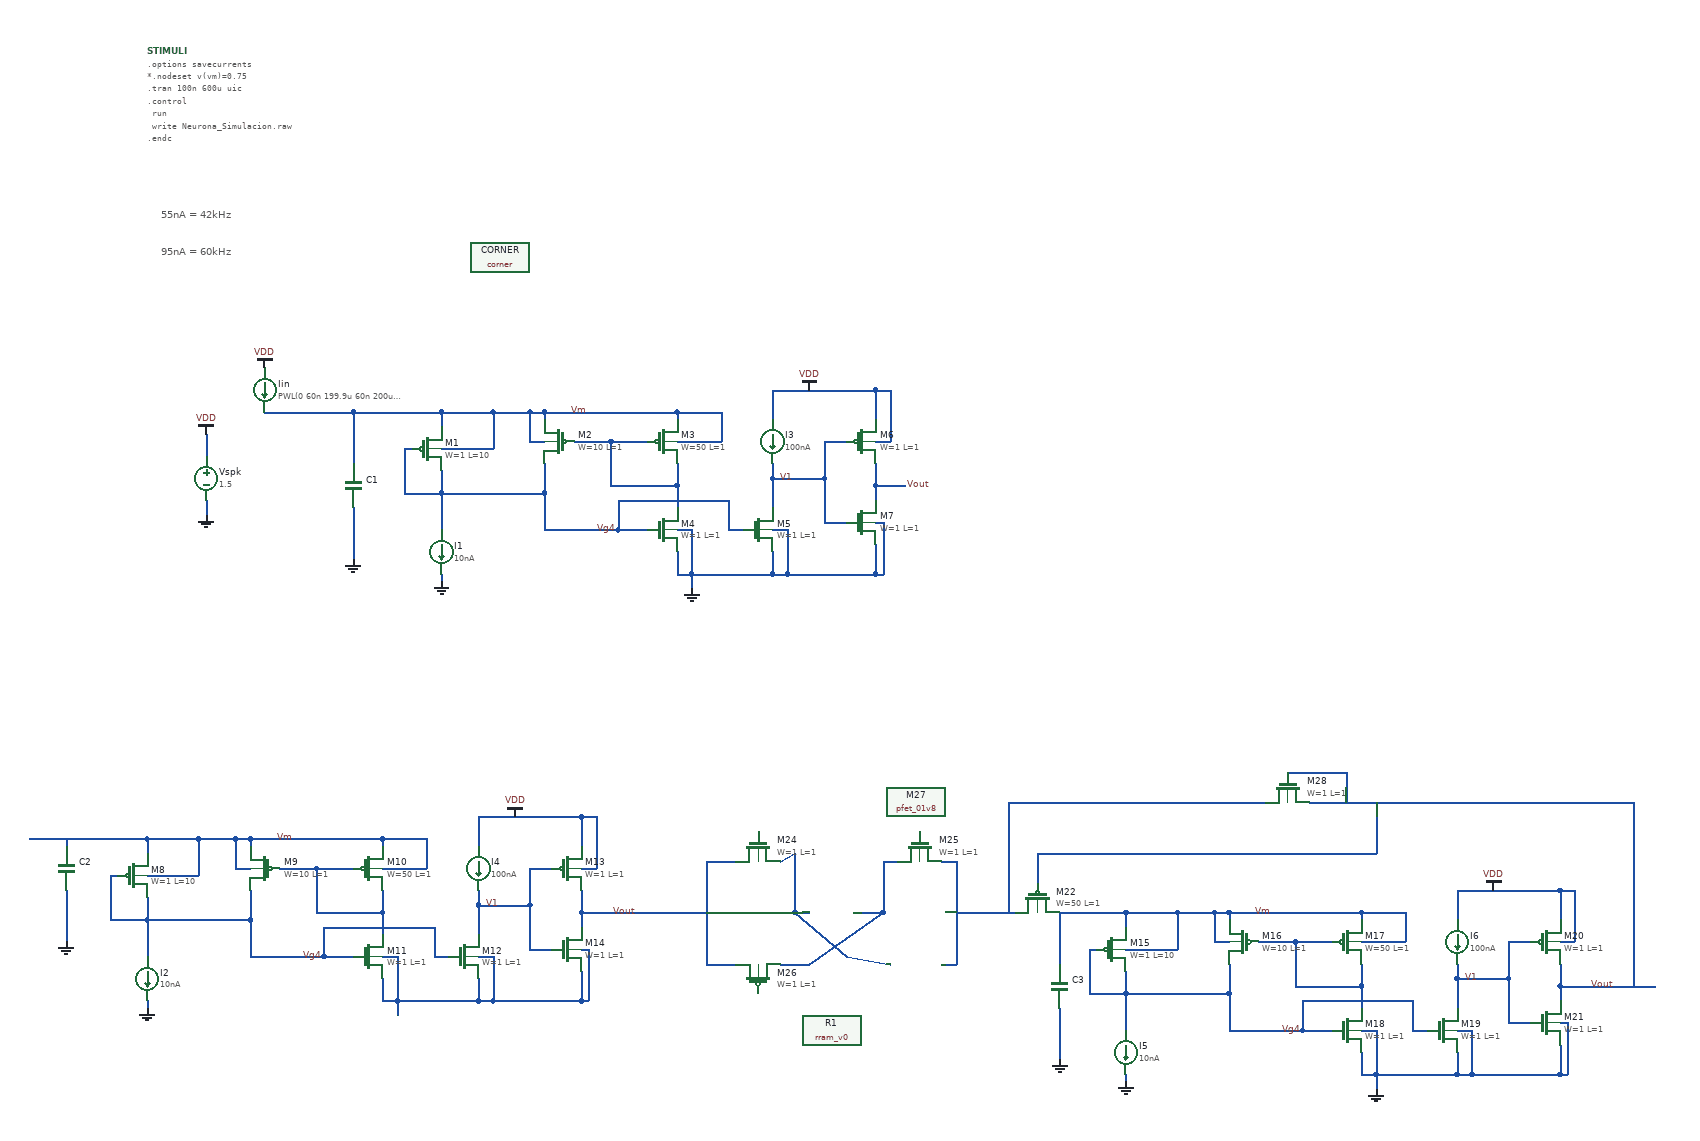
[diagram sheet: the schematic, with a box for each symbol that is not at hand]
v {xschem version=3.4.5 file_version=1.2
}
G {}
K {}
V {}
S {}
E {}
B 2 1290 -460 2090 -60 {flags=graph
y1=1.4
y2=1.6
ypos1=-0.319016
ypos2=2.49867
divy=5
subdivy=1
unity=1
x1=0.000170408
x2=0.000221948
divx=5
subdivx=1
node=vout
color=7
dataset=-1
unitx=1
logx=0
logy=0
digital=0
linewidth_mult=3.5}
B 2 1290 -860 2090 -460 {flags=graph
y1=0.190995
y2=1.94705
ypos1=0
ypos2=2
divy=5
subdivy=1
unity=1
x1=0.000170408
x2=0.000221948
divx=5
subdivx=1


dataset=-1
unitx=1
logx=0
logy=0
color=4
node=vm}
B 2 450 -1130 1250 -730 {flags=graph


ypos1=0
ypos2=2
divy=5
subdivy=1
unity=1
x1=0.000170408
x2=0.000221948
divx=5
subdivx=1
node=vg4
color=4
dataset=-1
unitx=1
logx=0
logy=0
y1=0.69
y2=0.7}
B 2 1290 -1260 2090 -860 {flags=graph
y1=2.17444e-08
y2=1.41183e-07
ypos1=0
ypos2=2
divy=5
subdivy=1
unity=1
x1=0.000170408
x2=0.000221948
divx=5
subdivx=1


dataset=-1
unitx=1
logx=0
logy=0
color=4
node="\\"Iin; i(@iin[current])\\""}
T {55nA = 42kHz} 160 -720 0 0 0.4 0.4 {}
T {95nA = 60kHz} 160 -670 0 0 0.4 0.4 {}
N 860 -440 860 -430 {
lab=Vm}
N 680 -440 680 -430 {
lab=Vm}
N 540 -440 540 -420 {
lab=Vm}
N 770 -400 820 -400 {
lab=#net1}
N 860 -340 860 -310 {
lab=#net1}
N 770 -340 860 -340 {
lab=#net1}
N 770 -400 770 -340 {
lab=#net1}
N 780 -280 820 -280 {
lab=Vg4}
N 680 -330 680 -280 {
lab=Vg4}
N 540 -360 540 -330 {
lab=Vg4}
N 540 -330 540 -280 {
lab=Vg4}
N 860 -250 860 -220 {
lab=GND}
N 990 -250 990 -220 {
lab=GND}
N 1130 -260 1130 -220 {
lab=GND}
N 1060 -350 1060 -290 {
lab=V1}
N 1060 -290 1090 -290 {
lab=V1}
N 1060 -400 1060 -350 {
lab=V1}
N 1060 -400 1090 -400 {
lab=V1}
N 1130 -340 1130 -320 {
lab=Vout}
N 1130 -290 1140 -290 {
lab=GND}
N 1140 -290 1140 -220 {
lab=GND}
N 1130 -220 1140 -220 {
lab=GND}
N 490 -390 500 -390 {
lab=Vg4}
N 540 -390 610 -390 {
lab=Vm}
N 1130 -470 1130 -430 {
lab=VDD}
N 540 -220 540 -210 {
lab=GND}
N 1130 -340 1170 -340 {
lab=Vout}
N 220 -410 220 -380 {
lab=VDD}
N 220 -320 220 -300 {
lab=GND}
N 860 -280 880 -280 {
lab=GND}
N 880 -280 880 -220 {
lab=GND}
N 990 -280 1010 -280 {
lab=GND}
N 1010 -280 1010 -220 {
lab=GND}
N 660 -400 680 -400 {
lab=Vm}
N 860 -400 920 -400 {
lab=Vm}
N 1130 -400 1150 -400 {
lab=VDD}
N 1150 -470 1150 -400 {
lab=VDD}
N 1130 -470 1150 -470 {
lab=VDD}
N 420 -440 540 -440 {
lab=Vm}
N 420 -440 420 -370 {
lab=Vm}
N 420 -310 420 -240 {
lab=GND}
N 490 -330 540 -330 {
lab=Vg4}
N 610 -440 610 -390 {
lab=Vm}
N 660 -440 660 -400 {
lab=Vm}
N 920 -440 920 -400 {
lab=Vm}
N 860 -440 920 -440 {
lab=Vm}
N 990 -350 990 -310 {
lab=V1}
N 990 -470 990 -430 {
lab=VDD}
N 880 -220 880 -200 {
lab=GND}
N 930 -280 950 -280 {
lab=Vg4}
N 930 -320 930 -280 {
lab=Vg4}
N 780 -320 930 -320 {
lab=Vg4}
N 780 -320 780 -280 {
lab=Vg4}
N 540 -330 680 -330 {
lab=Vg4}
N 680 -440 860 -440 {
lab=Vm}
N 490 -390 490 -330 {
lab=Vg4}
N 990 -470 1130 -470 {
lab=VDD}
N 990 -350 1060 -350 {
lab=V1}
N 1010 -220 1130 -220 {
lab=GND}
N 660 -440 680 -440 {
lab=Vm}
N 860 -370 860 -340 {
lab=#net1}
N 720 -400 770 -400 {
lab=#net1}
N 880 -220 990 -220 {
lab=GND}
N 1130 -370 1130 -340 {
lab=Vout}
N 860 -220 880 -220 {
lab=GND}
N 990 -220 1010 -220 {
lab=GND}
N 300 -440 420 -440 {
lab=Vm}
N 540 -440 610 -440 {
lab=Vm}
N 610 -440 660 -440 {
lab=Vm}
N 680 -280 780 -280 {
lab=Vg4}
N 680 -370 680 -330 {
lab=Vg4}
N 990 -370 990 -350 {
lab=V1}
N 460 140 460 150 {
lab=Vm}
N 280 140 280 150 {
lab=Vm}
N 140 140 140 160 {
lab=Vm}
N 370 180 420 180 {
lab=#net2}
N 460 240 460 270 {
lab=#net2}
N 370 240 460 240 {
lab=#net2}
N 370 180 370 240 {
lab=#net2}
N 380 300 420 300 {
lab=Vg4}
N 280 250 280 300 {
lab=Vg4}
N 140 220 140 250 {
lab=Vg4}
N 140 250 140 300 {
lab=Vg4}
N 460 330 460 360 {
lab=#net3}
N 590 330 590 360 {
lab=#net3}
N 730 320 730 360 {
lab=#net3}
N 660 230 660 290 {
lab=V1}
N 660 290 690 290 {
lab=V1}
N 660 180 660 230 {
lab=V1}
N 660 180 690 180 {
lab=V1}
N 730 240 730 260 {
lab=Vout}
N 730 290 740 290 {
lab=#net3}
N 740 290 740 360 {
lab=#net3}
N 730 360 740 360 {
lab=#net3}
N 90 190 100 190 {
lab=Vg4}
N 140 190 210 190 {
lab=Vm}
N 730 110 730 150 {
lab=VDD}
N 140 360 140 370 {
lab=GND}
N 730 240 770 240 {
lab=Vout}
N 460 300 480 300 {
lab=#net3}
N 480 300 480 360 {
lab=#net3}
N 590 300 610 300 {
lab=#net3}
N 610 300 610 360 {
lab=#net3}
N 260 180 280 180 {
lab=Vm}
N 460 180 520 180 {
lab=Vm}
N 730 180 750 180 {
lab=VDD}
N 750 110 750 180 {
lab=VDD}
N 730 110 750 110 {
lab=VDD}
N 90 250 140 250 {
lab=Vg4}
N 210 140 210 190 {
lab=Vm}
N 260 140 260 180 {
lab=Vm}
N 520 140 520 180 {
lab=Vm}
N 460 140 520 140 {
lab=Vm}
N 590 230 590 270 {
lab=V1}
N 590 110 590 150 {
lab=VDD}
N 480 360 480 380 {
lab=#net3}
N 530 300 550 300 {
lab=Vg4}
N 530 260 530 300 {
lab=Vg4}
N 380 260 530 260 {
lab=Vg4}
N 380 260 380 300 {
lab=Vg4}
N 140 250 280 250 {
lab=Vg4}
N 280 140 460 140 {
lab=Vm}
N 90 190 90 250 {
lab=Vg4}
N 590 110 730 110 {
lab=VDD}
N 590 230 660 230 {
lab=V1}
N 610 360 730 360 {
lab=#net3}
N 260 140 280 140 {
lab=Vm}
N 460 210 460 240 {
lab=#net2}
N 320 180 370 180 {
lab=#net2}
N 480 360 590 360 {
lab=#net3}
N 730 210 730 240 {
lab=Vout}
N 460 360 480 360 {
lab=#net3}
N 590 360 610 360 {
lab=#net3}
N 140 140 210 140 {
lab=Vm}
N 210 140 260 140 {
lab=Vm}
N 280 300 380 300 {
lab=Vg4}
N 280 210 280 250 {
lab=Vg4}
N 590 210 590 230 {
lab=V1}
N 900 170 940 170 {
lab=Vout}
N 900 170 900 310 {
lab=Vout}
N 900 310 940 310 {
lab=Vout}
N 1000 310 1040 310 {
lab=#net4}
N 1040 310 1140 240 {
lab=#net4}
N 1100 240 1140 240 {
lab=#net4}
N 1090 300 1150 310 {
lab=#net5}
N 1020 240 1090 300 {
lab=#net5}
N 1020 240 1040 240 {
lab=#net5}
N 1020 160 1020 240 {
lab=#net5}
N 1000 170 1020 160 {
lab=#net5}
N 1140 170 1160 170 {
lab=#net4}
N 1140 170 1140 240 {
lab=#net4}
N 1220 170 1240 170 {
lab=#net6}
N 1240 170 1240 310 {
lab=#net6}
N 1220 310 1240 310 {
lab=#net6}
N 770 240 890 240 {
lab=Vout}
N 890 240 900 240 {
lab=Vout}
N 1790 240 1790 250 {
lab=Vm}
N 1610 240 1610 250 {
lab=Vm}
N 1470 240 1470 260 {
lab=Vm}
N 1700 280 1750 280 {
lab=#net7}
N 1790 340 1790 370 {
lab=#net7}
N 1700 340 1790 340 {
lab=#net7}
N 1700 280 1700 340 {
lab=#net7}
N 1710 400 1750 400 {
lab=Vg4}
N 1610 350 1610 400 {
lab=Vg4}
N 1470 320 1470 350 {
lab=Vg4}
N 1470 350 1470 400 {
lab=Vg4}
N 1790 430 1790 460 {
lab=GND}
N 1920 430 1920 460 {
lab=GND}
N 2060 420 2060 460 {
lab=GND}
N 1990 330 1990 390 {
lab=V1}
N 1990 390 2020 390 {
lab=V1}
N 1990 280 1990 330 {
lab=V1}
N 1990 280 2020 280 {
lab=V1}
N 2060 340 2060 360 {
lab=Vout}
N 2060 390 2070 390 {
lab=GND}
N 2070 390 2070 460 {
lab=GND}
N 2060 460 2070 460 {
lab=GND}
N 1420 290 1430 290 {
lab=Vg4}
N 1470 290 1540 290 {
lab=Vm}
N 2060 210 2060 250 {
lab=VDD}
N 1470 460 1470 470 {
lab=GND}
N 2060 340 2100 340 {
lab=Vout}
N 1790 400 1810 400 {
lab=GND}
N 1810 400 1810 460 {
lab=GND}
N 1920 400 1940 400 {
lab=GND}
N 1940 400 1940 460 {
lab=GND}
N 1590 280 1610 280 {
lab=Vm}
N 1790 280 1850 280 {
lab=Vm}
N 2060 280 2080 280 {
lab=VDD}
N 2080 210 2080 280 {
lab=VDD}
N 2060 210 2080 210 {
lab=VDD}
N 1380 240 1380 310 {
lab=Vm}
N 1380 370 1380 440 {
lab=GND}
N 1420 350 1470 350 {
lab=Vg4}
N 1540 240 1540 290 {
lab=Vm}
N 1590 240 1590 280 {
lab=Vm}
N 1850 240 1850 280 {
lab=Vm}
N 1790 240 1850 240 {
lab=Vm}
N 1920 330 1920 370 {
lab=V1}
N 1920 210 1920 250 {
lab=VDD}
N 1810 460 1810 480 {
lab=GND}
N 1860 400 1880 400 {
lab=Vg4}
N 1860 360 1860 400 {
lab=Vg4}
N 1710 360 1860 360 {
lab=Vg4}
N 1710 360 1710 400 {
lab=Vg4}
N 1470 350 1610 350 {
lab=Vg4}
N 1610 240 1790 240 {
lab=Vm}
N 1420 290 1420 350 {
lab=Vg4}
N 1920 210 2060 210 {
lab=VDD}
N 1920 330 1990 330 {
lab=V1}
N 1940 460 2060 460 {
lab=GND}
N 1590 240 1610 240 {
lab=Vm}
N 1790 310 1790 340 {
lab=#net7}
N 1650 280 1700 280 {
lab=#net7}
N 1810 460 1920 460 {
lab=GND}
N 2060 310 2060 340 {
lab=Vout}
N 1790 460 1810 460 {
lab=GND}
N 1920 460 1940 460 {
lab=GND}
N 1470 240 1540 240 {
lab=Vm}
N 1540 240 1590 240 {
lab=Vm}
N 1610 400 1710 400 {
lab=Vg4}
N 1610 310 1610 350 {
lab=Vg4}
N 1920 310 1920 330 {
lab=V1}
N 2100 340 2190 340 {
lab=Vout}
N 2160 340 2190 340 {
lab=Vout}
N 2160 90 2160 340 {
lab=Vout}
N 1240 240 1270 240 {
lab=#net6}
N 1720 90 1880 90 {
lab=Vout}
N 1350 90 1660 90 {
lab=#net6}
N 1690 50 1770 50 {
lab=Vout}
N 1770 50 1770 90 {
lab=Vout}
N 1880 90 2160 90 {
lab=Vout}
N 1380 240 1470 240 {
lab=Vm}
N 1310 90 1350 90 {
lab=#net6}
N 1310 90 1310 240 {
lab=#net6}
N 1310 240 1320 240 {
lab=#net6}
N 1270 240 1320 240 {
lab=#net6}
N 1350 160 1350 200 {
lab=Vout}
N 1350 160 1810 160 {
lab=Vout}
N 1810 90 1810 160 {
lab=Vout}
N 30 210 30 280 {
lab=GND}
N -20 140 140 140 {
lab=Vm}
N 30 140 30 150 {
lab=Vm}
C {devices/title.sym} 170 -50 0 0 {name=l1 author="Stefan Schippers"}
C {sky130_fd_pr/pfet_01v8.sym} 520 -390 0 0 {name=M1
L=10
W=1
nf=1
mult=1
model=pfet_01v8
spiceprefix=X
}
C {sky130_fd_pr/pfet_01v8.sym} 700 -400 0 1 {name=M2
L=1
W=10
nf=1
mult=1
model=pfet_01v8
spiceprefix=X
}
C {sky130_fd_pr/pfet_01v8.sym} 840 -400 0 0 {name=M3
L=1
W=50
nf=1
mult=2
model=pfet_01v8
spiceprefix=X
}
C {sky130_fd_pr/nfet_01v8.sym} 840 -280 0 0 {name=M4
L=1
W=1
nf=1 
mult=1
model=nfet_01v8
spiceprefix=X
}
C {sky130_fd_pr/nfet_01v8.sym} 970 -280 0 0 {name=M5
L=1
W=1
nf=1 
mult=1
model=nfet_01v8
spiceprefix=X
}
C {sky130_fd_pr/pfet_01v8.sym} 1110 -400 0 0 {name=M6
L=1
W=1
nf=1
mult=1
model=pfet_01v8
spiceprefix=X
}
C {sky130_fd_pr/nfet_01v8.sym} 1110 -290 0 0 {name=M7
L=1
W=1
nf=1 
mult=1
model=nfet_01v8
spiceprefix=X
}
C {devices/isource.sym} 540 -250 0 0 {name=I1 value=10nA}
C {devices/gnd.sym} 540 -210 0 0 {name=l2 lab=GND}
C {devices/gnd.sym} 880 -200 0 0 {name=l3 lab=GND}
C {devices/lab_pin.sym} 1170 -340 0 1 {name=p2 sig_type=std_logic lab=Vout
}
C {devices/vsource.sym} 220 -350 0 0 {name=Vspk value=1.5}
C {devices/gnd.sym} 220 -300 0 0 {name=l5 lab=GND}
C {devices/lab_pin.sym} 740 -440 1 0 {name=p4 sig_type=std_logic lab=Vm}
C {sky130_fd_pr/corner.sym} 620 -650 0 0 {name=CORNER only_toplevel=true corner=tt}
C {devices/code_shown.sym} 140 -930 0 0 {name=STIMULI 
only_toplevel=true
place=end
value="
.options savecurrents
*.nodeset v(vm)=0.75
.tran 100n 600u uic
.control
	run
	write Neurona_Simulacion.raw
.endc
"}
C {devices/vdd.sym} 220 -410 0 0 {name=l6 lab=VDD}
C {devices/vdd.sym} 1040 -470 0 0 {name=l7 lab=VDD}
C {devices/capa.sym} 420 -340 0 0 {name=C1
m=1
value1=1p
footprint=1206
device="ceramic capacitor"}
C {devices/gnd.sym} 420 -240 0 0 {name=l8 lab=GND}
C {devices/isource.sym} 300 -470 0 0 {name=Iin value="PWL(0 60n 199.9u 60n 200u 75n 399.9u 75n 400u 90n)"}
C {devices/vdd.sym} 300 -500 0 0 {name=l4 lab=VDD}
C {devices/lab_pin.sym} 780 -280 3 0 {name=p1 sig_type=std_logic lab=Vg4}
C {devices/launcher.sym} 1130 -650 0 0 {name=h5
descr="load waves" 
tclcommand="xschem raw_read $netlist_dir/Neurona_Simulacion.raw tran"
}
C {devices/lab_pin.sym} 1020 -350 1 1 {name=p3 sig_type=std_logic lab=V1
}
C {devices/isource.sym} 990 -400 0 0 {name=I3 value=100nA

spice_ignore=false}
C {sky130_fd_pr/pfet_01v8.sym} 120 190 0 0 {name=M8
L=10
W=1
nf=1
mult=1
model=pfet_01v8
spiceprefix=X
}
C {sky130_fd_pr/pfet_01v8.sym} 300 180 0 1 {name=M9
L=1
W=10
nf=1
mult=1
model=pfet_01v8
spiceprefix=X
}
C {sky130_fd_pr/pfet_01v8.sym} 440 180 0 0 {name=M10
L=1
W=50
nf=1
mult=2
model=pfet_01v8
spiceprefix=X
}
C {sky130_fd_pr/nfet_01v8.sym} 440 300 0 0 {name=M11
L=1
W=1
nf=1 
mult=1
model=nfet_01v8
spiceprefix=X
}
C {sky130_fd_pr/nfet_01v8.sym} 570 300 0 0 {name=M12
L=1
W=1
nf=1 
mult=1
model=nfet_01v8
spiceprefix=X
}
C {sky130_fd_pr/pfet_01v8.sym} 710 180 0 0 {name=M13
L=1
W=1
nf=1
mult=1
model=pfet_01v8
spiceprefix=X
}
C {sky130_fd_pr/nfet_01v8.sym} 710 290 0 0 {name=M14
L=1
W=1
nf=1 
mult=1
model=nfet_01v8
spiceprefix=X
}
C {devices/isource.sym} 140 330 0 0 {name=I2 value=10nA}
C {devices/gnd.sym} 140 370 0 0 {name=l9 lab=GND}
C {devices/lab_pin.sym} 770 240 0 1 {name=p5 sig_type=std_logic lab=Vout
}
C {devices/lab_pin.sym} 340 140 1 0 {name=p6 sig_type=std_logic lab=Vm}
C {devices/vdd.sym} 640 110 0 0 {name=l10 lab=VDD}
C {devices/lab_pin.sym} 380 300 3 0 {name=p7 sig_type=std_logic lab=Vg4}
C {devices/lab_pin.sym} 620 230 1 1 {name=p8 sig_type=std_logic lab=V1
}
C {devices/isource.sym} 590 180 0 0 {name=I4 value=100nA

spice_ignore=false}
C {sky130_fd_pr/nfet_01v8.sym} 970 150 1 0 {name=M24
L=1
W=1
nf=1 
mult=1
model=nfet_01v8
spiceprefix=X
}
C {sky130_fd_pr/nfet_01v8.sym} 1190 150 1 0 {name=M25
L=1
W=1
nf=1 
mult=1
model=nfet_01v8
spiceprefix=X
}
C {sky130_fd_pr/pfet_01v8.sym} 970 330 3 0 {name=M26
L=1
W=1
nf=1
mult=1
model=pfet_01v8
spiceprefix=X
}
C {sky130_fd_pr/pfet_01v8.sym} 1190 330 3 0 {name=M27
L=1
W=1
nf=1
mult=1
model=pfet_01v8
spiceprefix=X
}
C {sky130_fd_pr/rram_v0.sym} 1070 240 1 0 {name=R1
model=rram_v0
spiceprefix=X
}
C {sky130_fd_pr/pfet_01v8.sym} 1450 290 0 0 {name=M15
L=10
W=1
nf=1
mult=1
model=pfet_01v8
spiceprefix=X
}
C {sky130_fd_pr/pfet_01v8.sym} 1630 280 0 1 {name=M16
L=1
W=10
nf=1
mult=1
model=pfet_01v8
spiceprefix=X
}
C {sky130_fd_pr/pfet_01v8.sym} 1770 280 0 0 {name=M17
L=1
W=50
nf=1
mult=2
model=pfet_01v8
spiceprefix=X
}
C {sky130_fd_pr/nfet_01v8.sym} 1770 400 0 0 {name=M18
L=1
W=1
nf=1 
mult=1
model=nfet_01v8
spiceprefix=X
}
C {sky130_fd_pr/nfet_01v8.sym} 1900 400 0 0 {name=M19
L=1
W=1
nf=1 
mult=1
model=nfet_01v8
spiceprefix=X
}
C {sky130_fd_pr/pfet_01v8.sym} 2040 280 0 0 {name=M20
L=1
W=1
nf=1
mult=1
model=pfet_01v8
spiceprefix=X
}
C {sky130_fd_pr/nfet_01v8.sym} 2040 390 0 0 {name=M21
L=1
W=1
nf=1 
mult=1
model=nfet_01v8
spiceprefix=X
}
C {devices/isource.sym} 1470 430 0 0 {name=I5 value=10nA}
C {devices/gnd.sym} 1470 470 0 0 {name=l13 lab=GND}
C {devices/gnd.sym} 1810 480 0 0 {name=l14 lab=GND}
C {devices/lab_pin.sym} 2100 340 0 1 {name=p9 sig_type=std_logic lab=Vout
}
C {devices/lab_pin.sym} 1670 240 1 0 {name=p10 sig_type=std_logic lab=Vm}
C {devices/vdd.sym} 1970 210 0 0 {name=l15 lab=VDD}
C {devices/capa.sym} 1380 340 0 0 {name=C3
m=1
value1=1p
footprint=1206
device="ceramic capacitor"}
C {devices/gnd.sym} 1380 440 0 0 {name=l16 lab=GND}
C {devices/lab_pin.sym} 1710 400 3 0 {name=p11 sig_type=std_logic lab=Vg4}
C {devices/lab_pin.sym} 1950 330 1 1 {name=p12 sig_type=std_logic lab=V1
}
C {devices/isource.sym} 1920 280 0 0 {name=I6 value=100nA

spice_ignore=false}
C {sky130_fd_pr/nfet_01v8.sym} 1690 70 1 0 {name=M28
L=1
W=1
nf=1 
mult=1
model=nfet_01v8
spiceprefix=X
}
C {sky130_fd_pr/pfet_01v8.sym} 1350 220 1 0 {name=M22
L=1
W=50
nf=1
mult=2
model=pfet_01v8
spiceprefix=X
}
C {devices/capa.sym} 30 180 0 0 {name=C2
m=1
value1=1p
footprint=1206
device="ceramic capacitor"}
C {devices/gnd.sym} 30 280 0 0 {name=l11 lab=GND}
